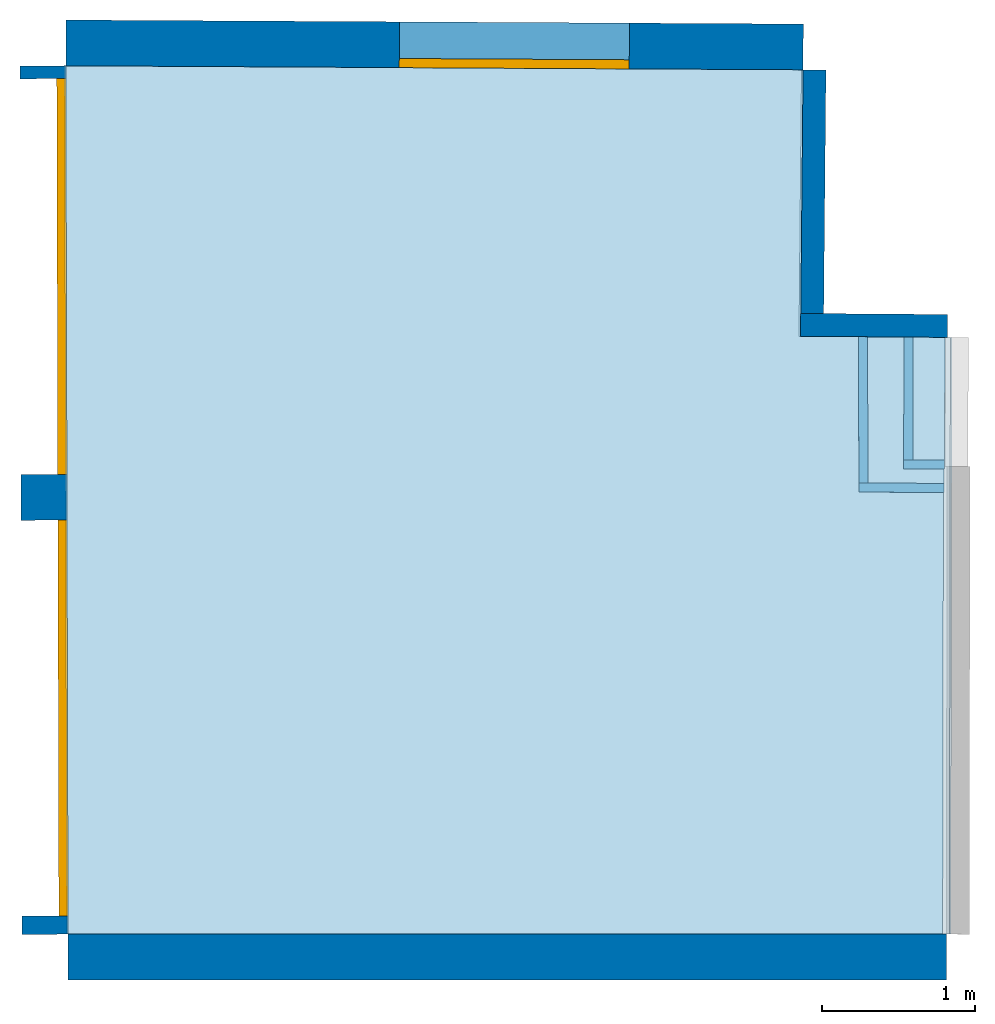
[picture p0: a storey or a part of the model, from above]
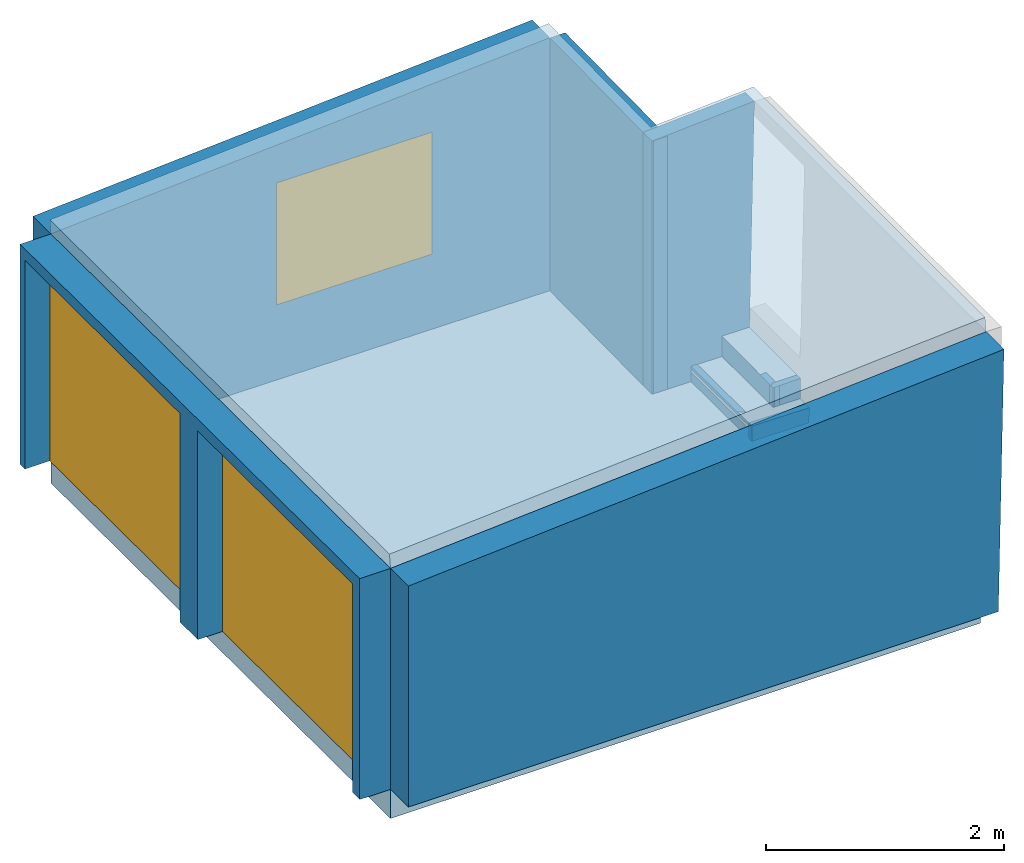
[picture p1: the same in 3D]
Properties of the parts of a building model (IFC2X3)

# File
Description: ViewDefinition[CoordinationView_V2.0]
File name: C:\Users\m.thoma\OneDrive - Hottgenroth Software AG\Desktop\Garage.ifc
Time: 2023-07-28T12:19:54
Written by: IFC 2x3 writer version 1.1
Made in: IFCExportDemo.exe

# IfcBuildingStorey, 600 EG
In: Vorführung
Elevation: 0 m

# IfcDoor (2)
In: 600 EG
OverallHeight: 2.14316 m; OverallWidth: 2.59256 m

# IfcSlab (3)
In: 600 EG
PredefinedType: FLOOR

# IfcWindow, Window
In: 600 EG
OverallHeight: 1.25257 m; OverallWidth: 1.50712 m
